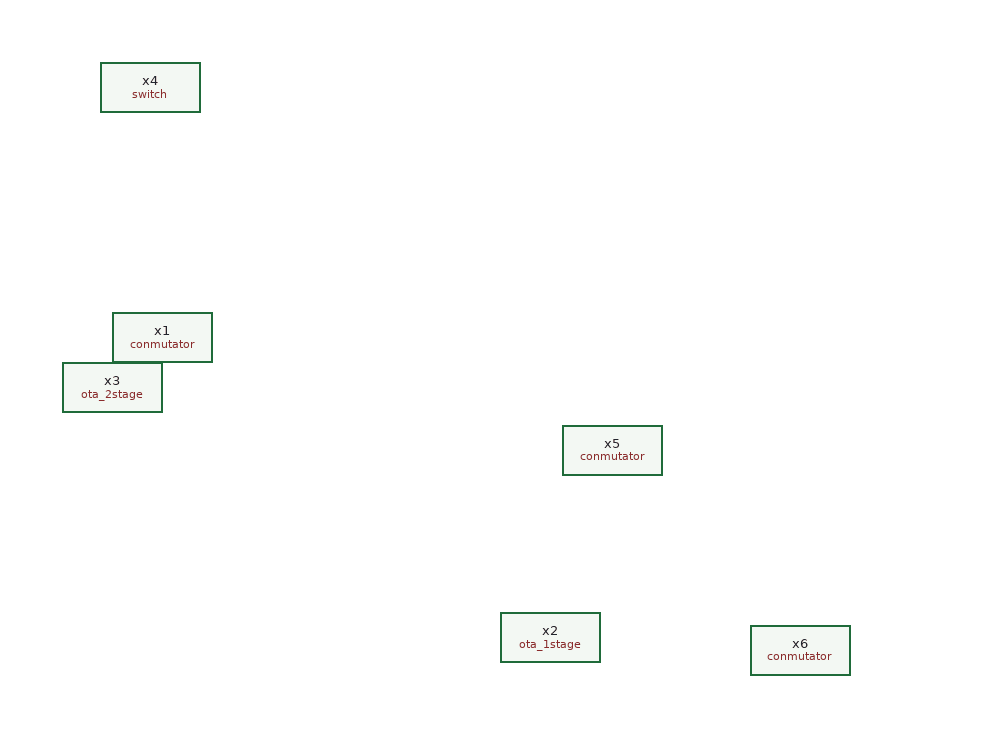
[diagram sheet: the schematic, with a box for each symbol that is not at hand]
v {xschem version=3.4.7 file_version=1.2}
G {}
K {}
V {}
S {}
E {}
C {designs/libs/core_conmutator/conmutator.sym} 70 110 0 1 {name=x1}
C {designs/libs/core_ota_1stage/ota_1stage.sym} 380 350 0 1 {name=x2}
C {designs/libs/core_ota_2stage/ota_2stage.sym} 30 150 0 0 {name=x3}
C {designs/libs/core_switch/switch.sym} 60 -90 0 0 {name=x4}
C {designs/libs/core_conmutator/conmutator.sym} 430 200 0 0 {name=x5}
C {designs/libs/core_conmutator/conmutator.sym} 580 360 0 0 {name=x6}
